VERSION 5.8 ;
BUSBITCHARS "[]" ;
DIVIDERCHAR "/" ;
UNITS
    DATABASE MICRONS 1000 ;
END UNITS

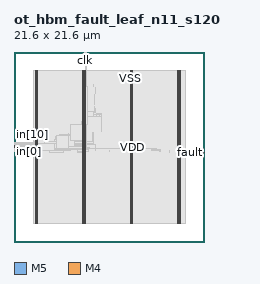
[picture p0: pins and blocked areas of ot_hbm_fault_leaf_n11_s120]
MACRO ot_hbm_fault_leaf_n11_s120
  FOREIGN ot_hbm_fault_leaf_n11_s120 0 0 ;
  CLASS BLOCK ;
  SIZE 21.6 BY 21.6 ;
  PIN clk
    DIRECTION INPUT ;
    USE SIGNAL ;
    PORT
      LAYER M5 ;
        RECT  8.016 21.516 8.04 21.6 ;
    END
  END clk
  PIN fault
    DIRECTION OUTPUT ;
    USE SIGNAL ;
    PORT
      LAYER M4 ;
        RECT  21.516 10.128 21.6 10.152 ;
    END
    PORT
      LAYER M4 ;
        RECT  20.473 10.128 21.564 10.152 ;
    END
  END fault
  PIN in[0]
    DIRECTION INPUT ;
    USE SIGNAL ;
    PORT
      LAYER M4 ;
        RECT  0 10.32 0.084 10.344 ;
    END
  END in[0]
  PIN in[10]
    DIRECTION INPUT ;
    USE SIGNAL ;
    PORT
      LAYER M4 ;
        RECT  0 11.28 0.084 11.304 ;
    END
  END in[10]
  PIN in[1]
    DIRECTION INPUT ;
    USE SIGNAL ;
    PORT
      LAYER M4 ;
        RECT  0 10.416 0.084 10.44 ;
    END
  END in[1]
  PIN in[2]
    DIRECTION INPUT ;
    USE SIGNAL ;
    PORT
      LAYER M4 ;
        RECT  0 10.512 0.084 10.536 ;
    END
  END in[2]
  PIN in[3]
    DIRECTION INPUT ;
    USE SIGNAL ;
    PORT
      LAYER M4 ;
        RECT  0 10.608 0.084 10.632 ;
    END
  END in[3]
  PIN in[4]
    DIRECTION INPUT ;
    USE SIGNAL ;
    PORT
      LAYER M4 ;
        RECT  0 10.704 0.084 10.728 ;
    END
  END in[4]
  PIN in[5]
    DIRECTION INPUT ;
    USE SIGNAL ;
    PORT
      LAYER M4 ;
        RECT  0 10.8 0.084 10.824 ;
    END
  END in[5]
  PIN in[6]
    DIRECTION INPUT ;
    USE SIGNAL ;
    PORT
      LAYER M4 ;
        RECT  0 10.896 0.084 10.92 ;
    END
  END in[6]
  PIN in[7]
    DIRECTION INPUT ;
    USE SIGNAL ;
    PORT
      LAYER M4 ;
        RECT  0 10.992 0.084 11.016 ;
    END
  END in[7]
  PIN in[8]
    DIRECTION INPUT ;
    USE SIGNAL ;
    PORT
      LAYER M4 ;
        RECT  0 11.088 0.084 11.112 ;
    END
  END in[8]
  PIN in[9]
    DIRECTION INPUT ;
    USE SIGNAL ;
    PORT
      LAYER M4 ;
        RECT  0 11.184 0.084 11.208 ;
    END
  END in[9]
  PIN rst_n
    DIRECTION INPUT ;
    USE SIGNAL ;
    PORT
      LAYER M5 ;
        RECT  8.112 21.516 8.136 21.6 ;
    END
  END rst_n
  PIN VDD
    DIRECTION INOUT ;
    USE POWER ;
    PORT
      LAYER M5 ;
        RECT  18.792 2.151 18.912 19.449 ;
        RECT  13.392 2.151 13.512 19.449 ;
        RECT  7.992 2.151 8.112 19.449 ;
        RECT  2.592 2.151 2.712 19.449 ;
    END
  END VDD
  PIN VSS
    DIRECTION INOUT ;
    USE GROUND ;
    PORT
      LAYER M5 ;
        RECT  18.6 2.137 18.72 19.463 ;
        RECT  13.2 2.137 13.32 19.463 ;
        RECT  7.8 2.137 7.92 19.463 ;
        RECT  2.4 2.137 2.52 19.463 ;
    END
  END VSS
  # OT_OBS_CLOSED layer=M5 d_um=1.536 added=1
  OBS
    LAYER RVTN ;
     RECT  2.16 2.16 19.44 2.295 ;
     RECT  2.16 2.565 19.44 2.835 ;
     RECT  2.16 3.105 19.44 3.375 ;
     RECT  2.16 3.645 19.44 3.915 ;
     RECT  2.16 4.185 19.44 4.455 ;
     RECT  2.16 4.725 19.44 4.995 ;
     RECT  2.16 5.265 19.44 5.535 ;
     RECT  2.16 5.805 19.44 6.075 ;
     RECT  2.16 6.345 19.44 6.615 ;
     RECT  2.16 6.885 19.44 7.155 ;
     RECT  2.16 7.425 19.44 7.695 ;
     RECT  2.16 7.965 19.44 8.235 ;
     RECT  2.16 8.505 19.44 8.775 ;
     RECT  2.16 9.045 19.44 9.315 ;
     RECT  2.16 9.585 19.44 9.855 ;
     RECT  2.16 10.125 19.44 10.395 ;
     RECT  2.16 10.665 19.44 10.935 ;
     RECT  2.16 11.205 19.44 11.475 ;
     RECT  2.16 11.745 19.44 12.015 ;
     RECT  2.16 12.285 19.44 12.555 ;
     RECT  2.16 12.825 19.44 13.095 ;
     RECT  2.16 13.365 19.44 13.635 ;
     RECT  2.16 13.905 19.44 14.175 ;
     RECT  2.16 14.445 19.44 14.715 ;
     RECT  2.16 14.985 19.44 15.255 ;
     RECT  2.16 15.525 19.44 15.795 ;
     RECT  2.16 16.065 19.44 16.335 ;
     RECT  2.16 16.605 19.44 16.875 ;
     RECT  2.16 17.145 19.44 17.415 ;
     RECT  2.16 17.685 19.44 17.955 ;
     RECT  2.16 18.225 19.44 18.495 ;
     RECT  2.16 18.765 19.44 19.035 ;
     RECT  2.16 19.305 19.44 19.44 ;
    LAYER RVTP ;
     RECT  2.16 2.295 19.44 2.565 ;
     RECT  2.16 2.835 19.44 3.105 ;
     RECT  2.16 3.375 19.44 3.645 ;
     RECT  2.16 3.915 19.44 4.185 ;
     RECT  2.16 4.455 19.44 4.725 ;
     RECT  2.16 4.995 19.44 5.265 ;
     RECT  2.16 5.535 19.44 5.805 ;
     RECT  2.16 6.075 19.44 6.345 ;
     RECT  2.16 6.615 19.44 6.885 ;
     RECT  2.16 7.155 19.44 7.425 ;
     RECT  2.16 7.695 19.44 7.965 ;
     RECT  2.16 8.235 19.44 8.505 ;
     RECT  2.16 8.775 19.44 9.045 ;
     RECT  2.16 9.315 19.44 9.585 ;
     RECT  2.16 9.855 19.44 10.125 ;
     RECT  2.16 10.395 19.44 10.665 ;
     RECT  2.16 10.935 19.44 11.205 ;
     RECT  2.16 11.475 19.44 11.745 ;
     RECT  2.16 12.015 19.44 12.285 ;
     RECT  2.16 12.555 19.44 12.825 ;
     RECT  2.16 13.095 19.44 13.365 ;
     RECT  2.16 13.635 19.44 13.905 ;
     RECT  2.16 14.175 19.44 14.445 ;
     RECT  2.16 14.715 19.44 14.985 ;
     RECT  2.16 15.255 19.44 15.525 ;
     RECT  2.16 15.795 19.44 16.065 ;
     RECT  2.16 16.335 19.44 16.605 ;
     RECT  2.16 16.875 19.44 17.145 ;
     RECT  2.16 17.415 19.44 17.685 ;
     RECT  2.16 17.955 19.44 18.225 ;
     RECT  2.16 18.495 19.44 18.765 ;
     RECT  2.16 19.035 19.44 19.305 ;
    LAYER M1 ;
     RECT  2.16 2.151 19.44 19.449 ;
    LAYER M2 ;
     RECT  2.16 2.151 19.44 19.449 ;
     RECT  19.44 10.134 20.507 10.152 ;
    LAYER M3 ;
     RECT  2.415 2.143 2.505 2.413 ;
     RECT  7.815 2.143 7.905 2.413 ;
     RECT  13.215 2.143 13.305 2.413 ;
     RECT  18.615 2.143 18.705 2.413 ;
     RECT  20.484 10.12 20.502 10.157 ;
     RECT  7.815 2.413 8.097 10.165 ;
     RECT  4.032 10.165 4.59 10.201 ;
     RECT  5.652 10.165 5.67 10.201 ;
     RECT  7.2 10.165 8.097 10.291 ;
     RECT  2.415 2.413 2.697 10.315 ;
     RECT  16.596 10.327 16.614 10.399 ;
     RECT  10.836 10.291 10.854 10.427 ;
     RECT  17.64 10.201 17.658 10.427 ;
     RECT  2.304 10.315 2.697 10.435 ;
     RECT  4.032 10.201 5.67 10.435 ;
     RECT  16.2 10.399 16.614 10.435 ;
     RECT  15.624 10.435 16.614 10.463 ;
     RECT  4.032 10.435 6.39 10.471 ;
     RECT  7.2 10.291 8.478 10.471 ;
     RECT  4.032 10.471 8.478 10.597 ;
     RECT  9.288 10.435 9.306 10.597 ;
     RECT  15.624 10.463 16.218 10.637 ;
     RECT  2.304 10.435 3.15 10.651 ;
     RECT  4.032 10.597 9.306 10.651 ;
     RECT  16.2 10.637 16.218 10.661 ;
     RECT  0.144 10.651 0.162 10.829 ;
     RECT  2.304 10.651 9.306 11.129 ;
     RECT  2.304 11.129 8.982 11.165 ;
     RECT  2.304 11.165 2.697 11.435 ;
     RECT  3.42 11.165 8.982 11.435 ;
     RECT  3.42 11.435 3.438 11.507 ;
     RECT  4.572 11.435 8.097 11.705 ;
     RECT  4.68 11.705 8.097 11.975 ;
     RECT  5.148 11.975 8.097 12.209 ;
     RECT  5.148 12.209 5.166 12.245 ;
     RECT  6.156 12.209 6.354 12.245 ;
     RECT  6.156 12.245 6.174 12.317 ;
     RECT  7.164 12.209 8.097 12.317 ;
     RECT  8.964 11.435 8.982 12.479 ;
     RECT  7.815 12.317 8.097 12.523 ;
     RECT  7.815 12.523 8.262 12.749 ;
     RECT  7.815 12.749 8.226 13.091 ;
     RECT  7.815 13.091 8.097 13.291 ;
     RECT  7.632 13.291 8.097 13.667 ;
     RECT  9.9 12.523 9.918 13.945 ;
     RECT  9.9 13.945 9.954 14.251 ;
     RECT  9.684 14.251 9.954 14.485 ;
     RECT  9.36 14.485 9.954 14.639 ;
     RECT  9 14.755 9.306 14.813 ;
     RECT  9.144 14.813 9.306 15.179 ;
     RECT  9.144 15.179 9.162 15.449 ;
     RECT  9.108 15.601 9.126 16.799 ;
     RECT  9.216 16.915 9.234 17.609 ;
     RECT  7.815 13.667 8.097 17.659 ;
     RECT  9.072 17.725 9.09 17.879 ;
     RECT  7.815 17.659 8.154 18.031 ;
     RECT  7.815 18.031 8.298 18.149 ;
     RECT  2.415 11.435 2.697 19.187 ;
     RECT  13.215 2.413 13.497 19.187 ;
     RECT  18.615 2.413 18.897 19.187 ;
     RECT  2.415 19.187 2.505 19.457 ;
     RECT  7.815 18.149 8.154 19.457 ;
     RECT  13.215 19.187 13.305 19.457 ;
     RECT  18.615 19.187 18.705 19.457 ;
     RECT  8.136 19.457 8.154 19.565 ;
    LAYER M4 ;
     RECT  0.084 10.32 2.408 10.344 ;
     RECT  0.06 10.344 2.408 10.416 ;
     RECT  0.084 10.416 2.408 10.44 ;
     RECT  0.06 10.44 2.408 10.512 ;
     RECT  0.084 10.512 2.408 10.536 ;
     RECT  0.06 10.536 2.408 10.608 ;
     RECT  0.084 10.608 2.408 10.632 ;
     RECT  0.06 10.632 2.408 10.704 ;
     RECT  0.084 10.704 2.408 10.728 ;
     RECT  0.06 10.728 2.408 10.8 ;
     RECT  0.084 10.8 2.408 10.824 ;
     RECT  0.06 10.824 2.408 10.896 ;
     RECT  0.084 10.896 2.408 10.92 ;
     RECT  0.06 10.92 2.408 10.992 ;
     RECT  0.084 10.992 2.408 11.016 ;
     RECT  0.06 11.016 2.408 11.088 ;
     RECT  0.084 11.088 2.408 11.112 ;
     RECT  0.06 11.112 2.408 11.184 ;
     RECT  0.084 11.184 2.408 11.208 ;
     RECT  0.06 11.208 2.408 11.28 ;
     RECT  0.084 11.28 2.408 11.304 ;
     RECT  2.408 2.148 2.512 19.452 ;
     RECT  2.512 2.418 2.704 19.182 ;
     RECT  2.704 10.416 4.601 11.208 ;
     RECT  4.601 10.608 4.796 11.208 ;
     RECT  4.796 10.608 4.837 11.256 ;
     RECT  4.837 10.608 6.149 12.12 ;
     RECT  6.149 10.896 6.833 12.12 ;
     RECT  6.421 13.296 7.621 13.32 ;
     RECT  6.833 10.896 7.808 10.92 ;
     RECT  6.833 12 7.808 12.12 ;
     RECT  7.621 13.296 7.808 13.656 ;
     RECT  7.808 2.148 7.912 19.452 ;
     RECT  7.912 2.418 8.081 19.452 ;
     RECT  8.081 2.418 8.104 19.56 ;
     RECT  8.104 19.536 8.165 19.56 ;
     RECT  8.104 10.608 8.243 14.808 ;
     RECT  8.243 12.528 8.273 14.808 ;
     RECT  8.005 21.456 8.291 21.48 ;
     RECT  8.273 13.392 8.387 14.808 ;
     RECT  8.104 17.664 8.387 17.688 ;
     RECT  8.243 10.608 8.597 10.728 ;
     RECT  8.387 14.256 9.029 14.808 ;
     RECT  9.029 14.256 9.389 14.52 ;
     RECT  9.389 14.256 9.713 14.28 ;
     RECT  8.597 10.608 13.208 10.632 ;
     RECT  13.208 2.148 13.312 19.452 ;
     RECT  13.312 2.418 13.504 19.182 ;
     RECT  13.504 10.608 15.653 10.632 ;
     RECT  18.608 2.148 18.712 19.452 ;
     RECT  18.712 2.418 18.904 19.182 ;
    LAYER M5 ;
     RECT  2.4 2.137 2.52 2.151 ;
     RECT  7.8 2.137 7.92 2.151 ;
     RECT  13.2 2.137 13.32 2.151 ;
     RECT  18.6 2.137 18.72 2.151 ;
     RECT  7.8 2.151 8.112 11.173 ;
     RECT  4.848 11.221 4.872 12.131 ;
     RECT  6.432 11.509 6.456 13.331 ;
     RECT  7.8 11.173 8.232 13.381 ;
     RECT  7.8 13.381 8.376 17.699 ;
     RECT  2.4 2.151 2.712 19.449 ;
     RECT  13.2 2.151 13.512 19.449 ;
     RECT  18.6 2.151 18.912 19.449 ;
     RECT  2.4 19.449 2.52 19.463 ;
     RECT  7.8 17.699 8.28 19.463 ;
     RECT  13.2 19.449 13.32 19.463 ;
     RECT  18.6 19.449 18.72 19.463 ;
     RECT  8.112 19.463 8.28 21.445 ;
     RECT  8.016 21.445 8.28 21.491 ;
     RECT  8.016 21.491 8.136 21.516 ;
     RECT  8.04 21.516 8.112 21.584 ;
     RECT  6.456 11.509 7.8 13.331 ;
  END
END ot_hbm_fault_leaf_n11_s120
END LIBRARY
